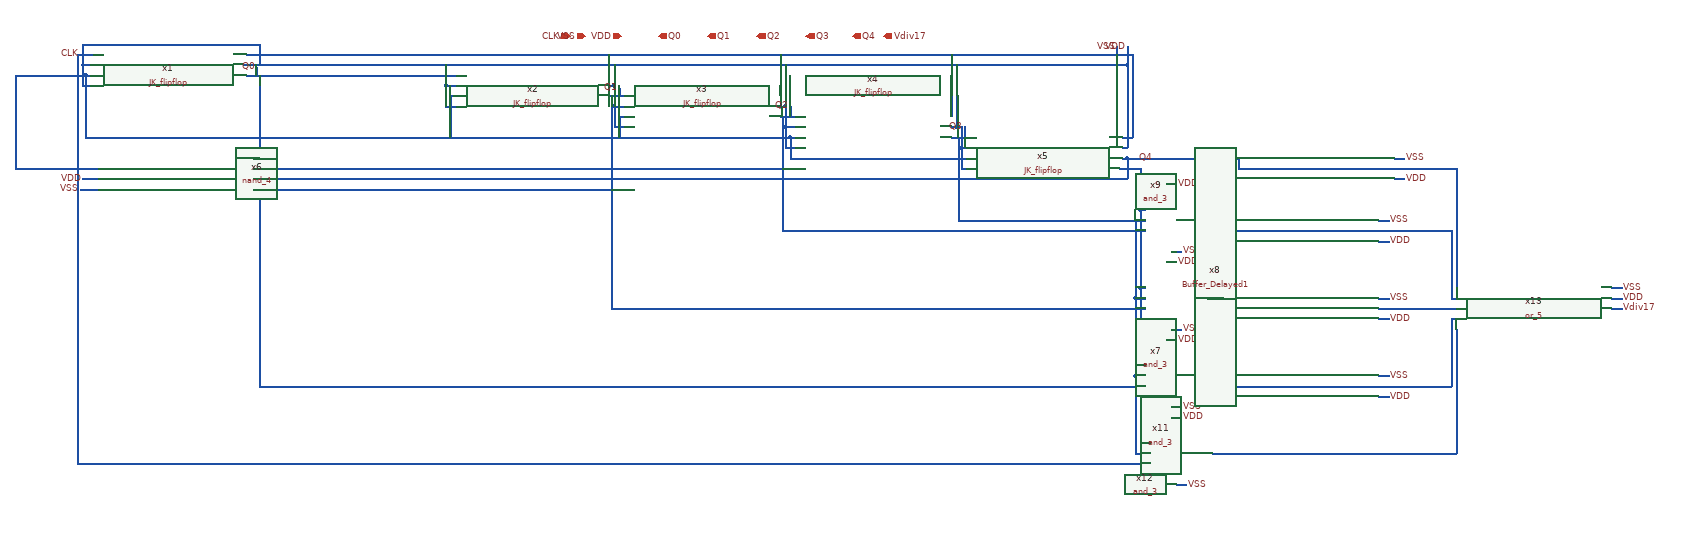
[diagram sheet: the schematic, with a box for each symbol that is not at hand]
v {xschem version=3.1.0 file_version=1.2
}
G {}
K {}
V {}
S {}
E {}
N -1375 -430 -1345 -430 {
lab=Q1}
N -1045 -390 -1015 -390 {
lab=Q2}
N -715 -350 -685 -350 {
lab=Q3}
N -385 -310 -375 -310 {
lab=Q4}
N -375 -310 -375 -270 {
lab=Q4}
N -1675 -270 -375 -270 {
lab=Q4}
N -2060 -270 -2040 -270 {
lab=Q4}
N -2385 -470 -2375 -470 {
lab=#net1}
N -1025 -310 -685 -310 {
lab=#net1}
N -1025 -350 -1025 -310 {
lab=#net1}
N -1025 -350 -1015 -350 {
lab=#net1}
N -2015 -350 -1025 -350 {
lab=#net1}
N -1355 -390 -1345 -390 {
lab=#net1}
N -1355 -390 -1355 -350 {
lab=#net1}
N -695 -330 -685 -330 {
lab=VDD}
N -695 -330 -695 -290 {
lab=VDD}
N -695 -290 -685 -290 {
lab=VDD}
N -1035 -370 -1015 -370 {
lab=VDD}
N -1035 -370 -1035 -330 {
lab=VDD}
N -1035 -330 -1015 -330 {
lab=VDD}
N -1365 -410 -1345 -410 {
lab=VDD}
N -1365 -410 -1365 -370 {
lab=VDD}
N -1365 -370 -1345 -370 {
lab=VDD}
N -1715 -490 -375 -490 {
lab=VDD}
N -375 -490 -375 -330 {
lab=VDD}
N -385 -330 -375 -330 {
lab=VDD}
N -715 -370 -705 -370 {
lab=VDD}
N -705 -490 -705 -370 {
lab=VDD}
N -1045 -410 -1035 -410 {
lab=VDD}
N -1035 -490 -1035 -410 {
lab=VDD}
N -1375 -450 -1365 -450 {
lab=VDD}
N -1365 -490 -1365 -450 {
lab=VDD}
N -1715 -510 -365 -510 {
lab=VSS}
N -365 -510 -365 -350 {
lab=VSS}
N -385 -350 -365 -350 {
lab=VSS}
N -715 -510 -715 -390 {
lab=VSS}
N -1045 -510 -1045 -430 {
lab=VSS}
N -1375 -510 -1375 -470 {
lab=VSS}
N -2075 -470 -2035 -470 {
lab=Q0}
N -1365 -450 -1365 -410 {
lab=VDD}
N -1035 -410 -1035 -370 {
lab=VDD}
N -705 -370 -695 -370 {
lab=VDD}
N -695 -370 -695 -330 {
lab=VDD}
N -2385 -350 -2375 -350 {
lab=#net1}
N -2390 -270 -2360 -270 {
lab=#net2}
N -395 -525 -395 -515 {
lab=VSS}
N -375 -525 -375 -515 {
lab=VDD}
N -395 -515 -395 -510 {
lab=VSS}
N -375 -515 -375 -490 {
lab=VDD}
N -2385 -490 -2375 -490 {
lab=VDD}
N -2390 -490 -2385 -490 {
lab=VDD}
N -2390 -490 -2390 -450 {
lab=VDD}
N -2390 -450 -2375 -450 {
lab=VDD}
N -2055 -485 -2055 -470 {
lab=Q0}
N -1355 -445 -1355 -430 {
lab=Q1}
N -1025 -410 -1025 -390 {
lab=Q2}
N -690 -370 -690 -350 {
lab=Q3}
N -375 -310 -355 -310 {
lab=Q4}
N -280 -130 -270 -130 {
lab=VSS}
N -300 -260 -280 -260 {
lab=VDD}
N -290 -130 -280 -130 {
lab=VSS}
N 570 -60 580 -60 {
lab=VSS}
N 560 -40 580 -40 {
lab=VDD}
N 560 -60 570 -60 {
lab=VSS}
N 560 -20 580 -20 {
lab=Vdiv17}
N -2040 -270 -2035 -270 {
lab=Q4}
N -355 -310 -350 -310 {
lab=Q4}
N -390 -290 -350 -290 {
lab=#net3}
N -350 -290 -350 -210 {
lab=#net3}
N -350 -210 -340 -210 {
lab=#net3}
N -700 -350 -700 -190 {
lab=Q3}
N -700 -190 -340 -190 {
lab=Q3}
N -1040 -390 -1040 -170 {
lab=Q2}
N -1040 -170 -340 -170 {
lab=Q2}
N -280 20 -270 20 {
lab=VSS}
N -300 -110 -280 -110 {
lab=VDD}
N -290 20 -280 20 {
lab=VSS}
N -350 -60 -340 -60 {
lab=#net3}
N -350 -210 -350 -60 {
lab=#net3}
N -360 -190 -360 -40 {
lab=Q3}
N -360 -40 -340 -40 {
lab=Q3}
N -1370 -430 -1370 -20 {
lab=Q1}
N -1370 -20 -340 -20 {
lab=Q1}
N -280 170 -270 170 {
lab=VSS}
N -300 40 -280 40 {
lab=VDD}
N -290 170 -280 170 {
lab=VSS}
N -350 90 -340 90 {
lab=#net3}
N -360 110 -340 110 {
lab=Q3}
N -350 -60 -350 90 {
lab=#net3}
N -360 -40 -360 110 {
lab=Q3}
N -1690 130 -340 130 {
lab=Q0}
N -270 320 -260 320 {
lab=VSS}
N -290 190 -270 190 {
lab=VDD}
N -280 320 -270 320 {
lab=VSS}
N -340 240 -330 240 {
lab=#net3}
N -350 260 -330 260 {
lab=Q3}
N -2400 -510 -2400 280 {
lab=VDD}
N -2040 280 -330 280 {
lab=VDD}
N -350 90 -350 240 {
lab=#net3}
N -350 240 -340 240 {
lab=#net3}
N -360 260 -350 260 {
lab=Q3}
N -360 110 -360 260 {
lab=Q3}
N 210 -20 260 -20 {
lab=#net4}
N -350 -310 -190 -310 {
lab=Q4}
N 260 -290 260 -60 {
lab=Q4}
N 250 -40 260 -40 {
lab=#net5}
N 250 -170 250 -40 {
lab=#net5}
N 210 -170 250 -170 {
lab=#net5}
N 250 0 260 0 {
lab=#net6}
N 250 0 250 130 {
lab=#net6}
N 210 130 250 130 {
lab=#net6}
N -220 110 -190 110 {
lab=#net6}
N -220 -40 -190 -40 {
lab=#net7}
N -220 -190 -190 -190 {
lab=#net5}
N 110 -20 210 -20 {
lab=#net4}
N 110 130 210 130 {
lab=#net6}
N 110 -170 210 -170 {
lab=#net5}
N -210 260 260 260 {
lab=#net8}
N 260 20 260 260 {
lab=#net8}
N 120 -190 130 -190 {
lab=VSS}
N 110 -150 130 -150 {
lab=VDD}
N 110 -190 120 -190 {
lab=VSS}
N 120 -40 130 -40 {
lab=VSS}
N 110 0 130 0 {
lab=VDD}
N 110 -40 120 -40 {
lab=VSS}
N 120 110 130 110 {
lab=VSS}
N 110 150 130 150 {
lab=VDD}
N 110 110 120 110 {
lab=VSS}
N -190 130 110 130 {
lab=#net6}
N -190 110 -190 130 {
lab=#net6}
N 140 -290 260 -290 {
lab=Q4}
N -190 -310 -160 -310 {
lab=Q4}
N 150 -310 160 -310 {
lab=VSS}
N 140 -270 160 -270 {
lab=VDD}
N 140 -310 150 -310 {
lab=VSS}
N -160 -290 140 -290 {
lab=Q4}
N -160 -310 -160 -290 {
lab=Q4}
N -190 -170 110 -170 {
lab=#net5}
N -190 -190 -190 -170 {
lab=#net5}
N -2390 -530 -2050 -530 {
lab=VDD}
N -2050 -530 -2050 -490 {
lab=VDD}
N -2400 -510 -2370 -510 {
lab=VDD}
N -2390 -530 -2390 -490 {
lab=VDD}
N -1690 -450 -1670 -450 {
lab=VDD}
N -1690 -450 -1690 -410 {
lab=VDD}
N -1690 -410 -1670 -410 {
lab=VDD}
N -1710 -470 -1670 -470 {
lab=Q0}
N -1690 -490 -1690 -450 {
lab=VDD}
N -2080 -490 -2070 -490 {
lab=VDD}
N -2075 -510 -1715 -510 {
lab=VSS}
N -2070 -490 -1715 -490 {
lab=VDD}
N -2035 -270 -1675 -270 {
lab=Q4}
N -2375 -350 -2015 -350 {
lab=#net1}
N -1680 -430 -1675 -430 {
lab=#net1}
N -1680 -430 -1680 -350 {
lab=#net1}
N -2050 130 -1690 130 {
lab=Q0}
N -2400 280 -2040 280 {
lab=VDD}
N -2035 -470 -2030 -470 {
lab=Q0}
N -2030 -470 -1710 -470 {
lab=Q0}
N -2385 -470 -2385 -350 {
lab=#net1}
N -2520 -470 -2520 -300 {
lab=#net1}
N -2520 -470 -2385 -470 {
lab=#net1}
N -2050 -470 -2050 130 {
lab=Q0}
N -2510 -290 -2360 -290 {
lab=#net1}
N -2520 -290 -2510 -290 {
lab=#net1}
N -2520 -300 -2520 -290 {
lab=#net1}
N -2395 -250 -2360 -250 {
lab=VSS}
N -2060 -310 -2050 -310 {}
N -2060 -250 -1370 -250 {}
N -2060 -290 -1040 -290 {}
C {JK_flipflop.sym} -2225 -480 0 0 {name=x1}
C {JK_flipflop.sym} -1525 -440 0 0 {name=x2}
C {JK_flipflop.sym} -1195 -400 0 0 {name=x3}
C {JK_flipflop.sym} -865 -360 0 0 {name=x4}
C {JK_flipflop.sym} -535 -320 0 0 {name=x5}
C {devices/lab_wire.sym} -395 -525 1 0 {name=p7 sig_type=std_logic lab=VSS}
C {devices/lab_wire.sym} -375 -525 1 0 {name=p8 sig_type=std_logic lab=VDD}
C {devices/lab_wire.sym} -2395 -250 0 0 {name=p1 sig_type=std_logic lab=VSS}
C {devices/lab_wire.sym} -2390 -270 0 0 {name=p2 sig_type=std_logic lab=VDD}
C {devices/ipin.sym} -1450 -545 0 0 {name=p3 lab=CLK}
C {devices/iopin.sym} -1420 -545 0 0 {name=p4 lab=VSS
}
C {devices/iopin.sym} -1350 -545 0 0 {name=p5 lab=VDD}
C {devices/opin.sym} -1280 -545 0 0 {name=p18 lab=Q0}
C {devices/lab_pin.sym} -2395 -510 0 0 {name=p15 sig_type=std_logic lab=CLK}
C {devices/opin.sym} -1185 -545 0 0 {name=p6 lab=Q1}
C {devices/opin.sym} -1090 -545 0 0 {name=p9 lab=Q2}
C {devices/opin.sym} -995 -545 0 0 {name=p10 lab=Q3}
C {devices/opin.sym} -905 -545 0 0 {name=p11 lab=Q4}
C {devices/lab_pin.sym} -2055 -485 1 0 {name=p12 sig_type=std_logic lab=Q0}
C {devices/lab_pin.sym} -1355 -445 1 0 {name=p13 sig_type=std_logic lab=Q1}
C {devices/lab_pin.sym} -1025 -410 1 0 {name=p14 sig_type=std_logic lab=Q2}
C {devices/lab_pin.sym} -690 -370 1 0 {name=p16 sig_type=std_logic lab=Q3}
C {devices/lab_pin.sym} -355 -310 2 0 {name=p17 sig_type=std_logic lab=Q4}
C {devices/lab_pin.sym} -270 -130 2 0 {name=p20 sig_type=std_logic lab=VSS}
C {devices/lab_pin.sym} -280 -260 2 0 {name=p21 sig_type=std_logic lab=VDD}
C {devices/opin.sym} -845 -545 0 0 {name=p19 lab=Vdiv17}
C {devices/lab_pin.sym} 580 -60 2 0 {name=p24 sig_type=std_logic lab=VSS}
C {devices/lab_pin.sym} 580 -40 2 0 {name=p25 sig_type=std_logic lab=VDD}
C {devices/lab_pin.sym} 580 -20 2 0 {name=p29 sig_type=std_logic lab=Vdiv17}
C {and_3.sym} -400 -70 0 0 {name=x9}
C {devices/lab_pin.sym} -270 20 2 0 {name=p26 sig_type=std_logic lab=VSS}
C {devices/lab_pin.sym} -280 -110 2 0 {name=p27 sig_type=std_logic lab=VDD}
C {and_3.sym} -400 80 0 0 {name=x7}
C {devices/lab_pin.sym} -270 170 2 0 {name=p28 sig_type=std_logic lab=VSS}
C {devices/lab_pin.sym} -280 40 2 0 {name=p30 sig_type=std_logic lab=VDD}
C {and_3.sym} -400 230 0 0 {name=x11}
C {devices/lab_pin.sym} -260 320 2 0 {name=p31 sig_type=std_logic lab=VSS}
C {devices/lab_pin.sym} -270 190 2 0 {name=p32 sig_type=std_logic lab=VDD}
C {and_3.sym} -390 380 0 0 {name=x12}
C {or_5.sym} 410 -20 0 0 {name=x13}
C {devices/lab_pin.sym} 130 -190 2 0 {name=p22 sig_type=std_logic lab=VSS}
C {devices/lab_pin.sym} 130 -150 2 0 {name=p23 sig_type=std_logic lab=VDD}
C {devices/lab_pin.sym} 130 -40 2 0 {name=p33 sig_type=std_logic lab=VSS}
C {devices/lab_pin.sym} 130 0 2 0 {name=p34 sig_type=std_logic lab=VDD}
C {devices/lab_pin.sym} 130 110 2 0 {name=p35 sig_type=std_logic lab=VSS}
C {devices/lab_pin.sym} 130 150 2 0 {name=p36 sig_type=std_logic lab=VDD}
C {devices/lab_pin.sym} 160 -310 2 0 {name=p37 sig_type=std_logic lab=VSS}
C {devices/lab_pin.sym} 160 -270 2 0 {name=p38 sig_type=std_logic lab=VDD}
C {Buffer_Delayed1.sym} -40 -20 0 0 {name=x8}
C {nand_4.sym} -2210 -280 2 0 {name=x6}
